One B-rep face of a CAD part: STEP entity #80022.
In plain terms, the planar face has unit normal (0, 0, 1).
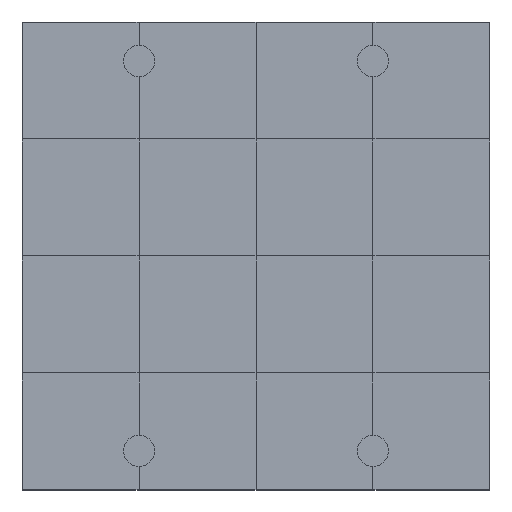
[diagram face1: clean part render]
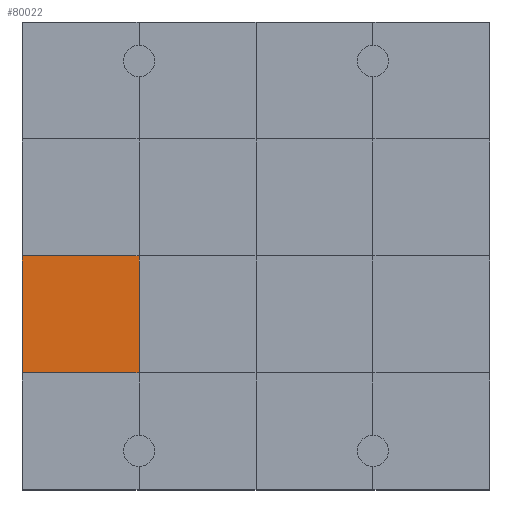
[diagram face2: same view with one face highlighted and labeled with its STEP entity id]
Its self-contained STEP definition (entity closure, numbers rounded to 3 decimals):
#79572 = VERTEX_POINT('',#79573);
#79573 = CARTESIAN_POINT('',(0.,3.,1.2));
#79587 = PLANE('',#79588);
#79588 = AXIS2_PLACEMENT_3D('',#79589,#79590,#79591);
#79589 = CARTESIAN_POINT('',(0.,3.,0.));
#79590 = DIRECTION('',(1.,0.,-0.));
#79591 = DIRECTION('',(0.,0.,1.));
#79613 = PLANE('',#79614);
#79614 = AXIS2_PLACEMENT_3D('',#79615,#79616,#79617);
#79615 = CARTESIAN_POINT('',(0.,0.,1.2));
#79616 = DIRECTION('',(0.,0.,1.));
#79617 = DIRECTION('',(1.,0.,-0.));
#79764 = VERTEX_POINT('',#79765);
#79765 = CARTESIAN_POINT('',(3.,3.,1.2));
#79786 = EDGE_CURVE('',#79572,#79764,#79787,.T.);
#79787 = SURFACE_CURVE('',#79788,(#79792,#79799),.PCURVE_S1.);
#79788 = LINE('',#79789,#79790);
#79789 = CARTESIAN_POINT('',(0.,3.,1.2));
#79790 = VECTOR('',#79791,1.);
#79791 = DIRECTION('',(1.,0.,-0.));
#79792 = PCURVE('',#79613,#79793);
#79793 = DEFINITIONAL_REPRESENTATION('',(#79794),#79798);
#79794 = LINE('',#79795,#79796);
#79795 = CARTESIAN_POINT('',(0.,3.));
#79796 = VECTOR('',#79797,1.);
#79797 = DIRECTION('',(1.,0.));
#79798 = ( GEOMETRIC_REPRESENTATION_CONTEXT(2) 
PARAMETRIC_REPRESENTATION_CONTEXT() REPRESENTATION_CONTEXT('2D SPACE',''
  ) );
#79799 = PCURVE('',#79800,#79805);
#79800 = PLANE('',#79801);
#79801 = AXIS2_PLACEMENT_3D('',#79802,#79803,#79804);
#79802 = CARTESIAN_POINT('',(0.,3.,1.2));
#79803 = DIRECTION('',(0.,0.,1.));
#79804 = DIRECTION('',(1.,0.,-0.));
#79805 = DEFINITIONAL_REPRESENTATION('',(#79806),#79810);
#79806 = LINE('',#79807,#79808);
#79807 = CARTESIAN_POINT('',(0.,0.));
#79808 = VECTOR('',#79809,1.);
#79809 = DIRECTION('',(1.,0.));
#79810 = ( GEOMETRIC_REPRESENTATION_CONTEXT(2) 
PARAMETRIC_REPRESENTATION_CONTEXT() REPRESENTATION_CONTEXT('2D SPACE',''
  ) );
#79845 = VERTEX_POINT('',#79846);
#79846 = CARTESIAN_POINT('',(0.,6.,1.2));
#79872 = EDGE_CURVE('',#79572,#79845,#79873,.T.);
#79873 = SURFACE_CURVE('',#79874,(#79878,#79885),.PCURVE_S1.);
#79874 = LINE('',#79875,#79876);
#79875 = CARTESIAN_POINT('',(0.,3.,1.2));
#79876 = VECTOR('',#79877,1.);
#79877 = DIRECTION('',(-0.,1.,0.));
#79878 = PCURVE('',#79587,#79879);
#79879 = DEFINITIONAL_REPRESENTATION('',(#79880),#79884);
#79880 = LINE('',#79881,#79882);
#79881 = CARTESIAN_POINT('',(1.2,0.));
#79882 = VECTOR('',#79883,1.);
#79883 = DIRECTION('',(0.,-1.));
#79884 = ( GEOMETRIC_REPRESENTATION_CONTEXT(2) 
PARAMETRIC_REPRESENTATION_CONTEXT() REPRESENTATION_CONTEXT('2D SPACE',''
  ) );
#79885 = PCURVE('',#79800,#79886);
#79886 = DEFINITIONAL_REPRESENTATION('',(#79887),#79891);
#79887 = LINE('',#79888,#79889);
#79888 = CARTESIAN_POINT('',(0.,0.));
#79889 = VECTOR('',#79890,1.);
#79890 = DIRECTION('',(0.,1.));
#79891 = ( GEOMETRIC_REPRESENTATION_CONTEXT(2) 
PARAMETRIC_REPRESENTATION_CONTEXT() REPRESENTATION_CONTEXT('2D SPACE',''
  ) );
#80022 = ADVANCED_FACE('',(#80023),#79800,.T.);
#80023 = FACE_BOUND('',#80024,.T.);
#80024 = EDGE_LOOP('',(#80025,#80026,#80027,#80055));
#80025 = ORIENTED_EDGE('',*,*,#79872,.F.);
#80026 = ORIENTED_EDGE('',*,*,#79786,.T.);
#80027 = ORIENTED_EDGE('',*,*,#80028,.T.);
#80028 = EDGE_CURVE('',#79764,#80029,#80031,.T.);
#80029 = VERTEX_POINT('',#80030);
#80030 = CARTESIAN_POINT('',(3.,6.,1.2));
#80031 = SURFACE_CURVE('',#80032,(#80036,#80043),.PCURVE_S1.);
#80032 = LINE('',#80033,#80034);
#80033 = CARTESIAN_POINT('',(3.,3.,1.2));
#80034 = VECTOR('',#80035,1.);
#80035 = DIRECTION('',(-0.,1.,0.));
#80036 = PCURVE('',#79800,#80037);
#80037 = DEFINITIONAL_REPRESENTATION('',(#80038),#80042);
#80038 = LINE('',#80039,#80040);
#80039 = CARTESIAN_POINT('',(3.,0.));
#80040 = VECTOR('',#80041,1.);
#80041 = DIRECTION('',(0.,1.));
#80042 = ( GEOMETRIC_REPRESENTATION_CONTEXT(2) 
PARAMETRIC_REPRESENTATION_CONTEXT() REPRESENTATION_CONTEXT('2D SPACE',''
  ) );
#80043 = PCURVE('',#80044,#80049);
#80044 = PLANE('',#80045);
#80045 = AXIS2_PLACEMENT_3D('',#80046,#80047,#80048);
#80046 = CARTESIAN_POINT('',(3.,3.,1.2));
#80047 = DIRECTION('',(0.,0.,1.));
#80048 = DIRECTION('',(1.,0.,-0.));
#80049 = DEFINITIONAL_REPRESENTATION('',(#80050),#80054);
#80050 = LINE('',#80051,#80052);
#80051 = CARTESIAN_POINT('',(0.,0.));
#80052 = VECTOR('',#80053,1.);
#80053 = DIRECTION('',(0.,1.));
#80054 = ( GEOMETRIC_REPRESENTATION_CONTEXT(2) 
PARAMETRIC_REPRESENTATION_CONTEXT() REPRESENTATION_CONTEXT('2D SPACE',''
  ) );
#80055 = ORIENTED_EDGE('',*,*,#80056,.F.);
#80056 = EDGE_CURVE('',#79845,#80029,#80057,.T.);
#80057 = SURFACE_CURVE('',#80058,(#80062,#80069),.PCURVE_S1.);
#80058 = LINE('',#80059,#80060);
#80059 = CARTESIAN_POINT('',(0.,6.,1.2));
#80060 = VECTOR('',#80061,1.);
#80061 = DIRECTION('',(1.,0.,-0.));
#80062 = PCURVE('',#79800,#80063);
#80063 = DEFINITIONAL_REPRESENTATION('',(#80064),#80068);
#80064 = LINE('',#80065,#80066);
#80065 = CARTESIAN_POINT('',(0.,3.));
#80066 = VECTOR('',#80067,1.);
#80067 = DIRECTION('',(1.,0.));
#80068 = ( GEOMETRIC_REPRESENTATION_CONTEXT(2) 
PARAMETRIC_REPRESENTATION_CONTEXT() REPRESENTATION_CONTEXT('2D SPACE',''
  ) );
#80069 = PCURVE('',#80070,#80075);
#80070 = PLANE('',#80071);
#80071 = AXIS2_PLACEMENT_3D('',#80072,#80073,#80074);
#80072 = CARTESIAN_POINT('',(0.,6.,1.2));
#80073 = DIRECTION('',(0.,0.,1.));
#80074 = DIRECTION('',(1.,0.,-0.));
#80075 = DEFINITIONAL_REPRESENTATION('',(#80076),#80080);
#80076 = LINE('',#80077,#80078);
#80077 = CARTESIAN_POINT('',(0.,0.));
#80078 = VECTOR('',#80079,1.);
#80079 = DIRECTION('',(1.,0.));
#80080 = ( GEOMETRIC_REPRESENTATION_CONTEXT(2) 
PARAMETRIC_REPRESENTATION_CONTEXT() REPRESENTATION_CONTEXT('2D SPACE',''
  ) );
